VERSION 5.7 ;
  NOWIREEXTENSIONATPIN ON ;
  DIVIDERCHAR "/" ;
  BUSBITCHARS "[]" ;
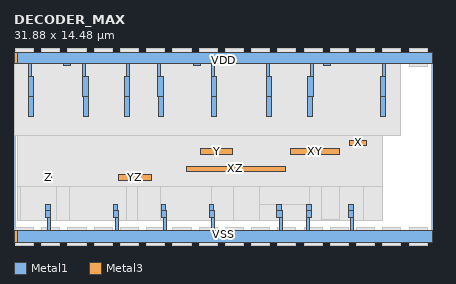
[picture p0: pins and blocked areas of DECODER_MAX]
MACRO DECODER_MAX
  CLASS BLOCK ;
  FOREIGN DECODER_MAX ;
  ORIGIN 1.260 0.000 ;
  SIZE 31.880 BY 14.480 ;
  PIN VSS
    DIRECTION INOUT ;
    USE GROUND ;
    PORT
      LAYER Metal1 ;
        RECT 1.140 2.380 1.500 2.880 ;
        RECT 6.300 2.380 6.660 2.880 ;
        RECT 9.960 2.380 10.320 2.880 ;
        RECT 13.620 2.380 13.980 2.880 ;
        RECT 18.780 2.380 19.140 2.880 ;
        RECT 21.060 2.380 21.420 2.880 ;
        RECT 1.140 1.880 1.530 2.380 ;
        RECT 6.300 1.880 6.690 2.380 ;
        RECT 9.960 1.880 10.350 2.380 ;
        RECT 13.620 1.880 14.010 2.380 ;
        RECT 18.780 1.880 19.170 2.380 ;
        RECT 1.300 0.900 1.530 1.880 ;
        RECT 6.460 0.900 6.690 1.880 ;
        RECT 10.120 0.900 10.350 1.880 ;
        RECT 13.780 0.900 14.010 1.880 ;
        RECT 18.940 0.900 19.170 1.880 ;
        RECT 21.030 1.880 21.420 2.380 ;
        RECT 24.220 2.380 24.580 2.880 ;
        RECT 24.220 1.880 24.610 2.380 ;
        RECT 21.030 0.900 21.260 1.880 ;
        RECT 24.380 0.900 24.610 1.880 ;
        RECT -1.000 0.000 30.620 0.900 ;
      LAYER Metal3 ;
        RECT -1.260 0.000 30.620 0.900 ;
    END
  END VSS
  PIN VDD
    DIRECTION INOUT ;
    USE POWER ;
    PORT
      LAYER Metal1 ;
        RECT -1.000 13.580 30.620 14.480 ;
        RECT -0.190 12.600 0.040 13.580 ;
        RECT 2.550 13.480 3.030 13.580 ;
        RECT 3.990 12.600 4.220 13.580 ;
        RECT 7.340 12.600 7.570 13.580 ;
        RECT -0.190 11.100 0.200 12.600 ;
        RECT 3.990 11.100 4.380 12.600 ;
        RECT -0.160 9.600 0.200 11.100 ;
        RECT 4.020 9.600 4.380 11.100 ;
        RECT 7.180 11.100 7.570 12.600 ;
        RECT 9.710 12.600 9.940 13.580 ;
        RECT 12.450 13.480 12.930 13.580 ;
        RECT 13.770 12.600 14.000 13.580 ;
        RECT 17.950 12.600 18.180 13.580 ;
        RECT 21.300 12.600 21.530 13.580 ;
        RECT 22.350 13.480 22.830 13.580 ;
        RECT 26.860 12.600 27.090 13.580 ;
        RECT 9.710 11.100 10.100 12.600 ;
        RECT 13.770 11.100 14.160 12.600 ;
        RECT 17.950 11.100 18.340 12.600 ;
        RECT 7.180 9.600 7.540 11.100 ;
        RECT 9.740 9.600 10.100 11.100 ;
        RECT 13.800 9.600 14.160 11.100 ;
        RECT 17.980 9.600 18.340 11.100 ;
        RECT 21.140 11.100 21.530 12.600 ;
        RECT 26.700 11.100 27.090 12.600 ;
        RECT 21.140 9.600 21.500 11.100 ;
        RECT 26.700 9.600 27.060 11.100 ;
      LAYER Metal3 ;
        RECT -1.260 13.580 30.620 14.480 ;
    END
  END VDD
  PIN Z
    DIRECTION OUTPUT ;
    ANTENNADIFFAREA 1.760000 ;
    PORT
      LAYER Metal3 ;
      RECT 1.200 4.720 1.600 5.120 ;
    END
  END Z
  PIN YZ
    DIRECTION INPUT ;
    ANTENNAGATEAREA 8.000000 ;
    PORT
      LAYER Metal3 ;
      RECT 6.730 4.720 9.230 5.120 ;
    END
  END YZ
  PIN XZ
    DIRECTION INPUT ;
    ANTENNAGATEAREA 8.000000 ;
    PORT
      LAYER Metal3 ;
      RECT 11.850 5.380 19.450 5.780 ;
    END
  END XZ
  PIN Y
    DIRECTION OUTPUT ;
    ANTENNADIFFAREA 1.760000 ;
    PORT
      LAYER Metal3 ;
      RECT 12.990 6.700 15.390 7.100 ;
    END
  END Y
  PIN XY
    DIRECTION INPUT ;
    ANTENNAGATEAREA 8.000000 ;
    PORT
      LAYER Metal3 ;
      RECT 19.810 6.700 23.510 7.100 ;
    END
  END XY
  PIN X
    DIRECTION OUTPUT ;
    ANTENNADIFFAREA 1.980000 ;
    PORT
      LAYER Metal3 ;
      RECT 24.310 7.360 25.610 7.760 ;
    END
  END X
  OBS
      LAYER Via1 ;
        RECT -1.150 -0.240 0.230 1.140 ;
        RECT 0.850 -0.240 2.230 1.140 ;
        RECT 2.850 -0.240 4.230 1.140 ;
        RECT 4.850 -0.240 6.230 1.140 ;
        RECT 6.850 -0.240 8.230 1.140 ;
        RECT 8.850 -0.240 10.230 1.140 ;
        RECT 10.850 -0.240 12.230 1.140 ;
        RECT 12.850 -0.240 14.230 1.140 ;
        RECT 14.850 -0.240 16.230 1.140 ;
        RECT 16.850 -0.240 18.230 1.140 ;
        RECT 18.850 -0.240 20.230 1.140 ;
        RECT 20.850 -0.240 22.230 1.140 ;
        RECT 22.850 -0.240 24.230 1.140 ;
        RECT 24.850 -0.240 26.230 1.140 ;
        RECT 26.850 -0.240 28.230 1.140 ;
        RECT 28.850 -0.240 30.230 1.140 ;
        RECT -1.010 1.650 26.860 12.830 ;
        RECT -1.150 13.340 0.230 14.720 ;
        RECT 0.850 13.340 2.230 14.720 ;
        RECT 2.850 13.340 4.230 14.720 ;
        RECT 4.850 13.340 6.230 14.720 ;
        RECT 6.850 13.340 8.230 14.720 ;
        RECT 8.850 13.340 10.230 14.720 ;
        RECT 10.850 13.340 12.230 14.720 ;
        RECT 12.850 13.340 14.230 14.720 ;
        RECT 14.850 13.340 16.230 14.720 ;
        RECT 16.850 13.340 18.230 14.720 ;
        RECT 18.850 13.340 20.230 14.720 ;
        RECT 20.850 13.340 22.230 14.720 ;
        RECT 22.850 13.340 24.230 14.720 ;
        RECT 24.850 13.340 26.230 14.720 ;
        RECT 26.850 13.340 28.230 14.720 ;
        RECT 28.850 13.340 30.230 14.720 ;
      LAYER Via2 ;
        RECT -1.150 -0.240 0.230 1.140 ;
        RECT 0.850 -0.240 2.230 1.140 ;
        RECT 2.850 -0.240 4.230 1.140 ;
        RECT 4.850 -0.240 6.230 1.140 ;
        RECT 6.850 -0.240 8.230 1.140 ;
        RECT 8.850 -0.240 10.230 1.140 ;
        RECT 10.850 -0.240 12.230 1.140 ;
        RECT 12.850 -0.240 14.230 1.140 ;
        RECT 14.850 -0.240 16.230 1.140 ;
        RECT 16.850 -0.240 18.230 1.140 ;
        RECT 18.850 -0.240 20.230 1.140 ;
        RECT 20.850 -0.240 22.230 1.140 ;
        RECT 22.850 -0.240 24.230 1.140 ;
        RECT 24.850 -0.240 26.230 1.140 ;
        RECT 26.850 -0.240 28.230 1.140 ;
        RECT 28.850 -0.240 30.230 1.140 ;
        RECT 22.155 1.700 23.515 4.540 ;
        RECT 5.115 7.940 6.475 11.780 ;
        RECT -1.010 4.230 26.810 11.780 ;
        RECT -1.150 13.340 0.230 14.720 ;
        RECT 0.850 13.340 2.230 14.720 ;
        RECT 2.850 13.340 4.230 14.720 ;
        RECT 4.850 13.340 6.230 14.720 ;
        RECT 6.850 13.340 8.230 14.720 ;
        RECT 8.850 13.340 10.230 14.720 ;
        RECT 10.850 13.340 12.230 14.720 ;
        RECT 12.850 13.340 14.230 14.720 ;
        RECT 14.850 13.340 16.230 14.720 ;
        RECT 16.850 13.340 18.230 14.720 ;
        RECT 18.850 13.340 20.230 14.720 ;
        RECT 20.850 13.340 22.230 14.720 ;
        RECT 22.850 13.340 24.230 14.720 ;
        RECT 24.850 13.340 26.230 14.720 ;
        RECT 26.850 13.340 28.230 14.720 ;
        RECT 28.850 13.340 30.230 14.720 ;
      LAYER Metal1 ;
        RECT 8.145 1.650 10.120 6.640 ;
        RECT 15.465 1.650 17.440 6.640 ;
        RECT 25.400 6.500 26.860 9.610 ;
        RECT -0.730 1.650 2.015 12.830 ;
        RECT 2.985 1.650 7.340 12.830 ;
        RECT 9.940 1.650 13.780 12.830 ;
        RECT 14.000 4.520 15.975 12.830 ;
        RECT 17.480 2.870 21.300 12.830 ;
        RECT 21.260 1.650 25.360 12.830 ;
      LAYER Metal2 ;
        RECT -1.150 -0.240 0.230 1.140 ;
        RECT 0.850 -0.240 2.230 1.140 ;
        RECT 2.850 -0.240 4.230 1.140 ;
        RECT 4.850 -0.240 6.230 1.140 ;
        RECT 6.850 -0.240 8.230 1.140 ;
        RECT 8.850 -0.240 10.230 1.140 ;
        RECT 10.850 -0.240 12.230 1.140 ;
        RECT 12.850 -0.240 14.230 1.140 ;
        RECT 14.850 -0.240 16.230 1.140 ;
        RECT 16.850 -0.240 18.230 1.140 ;
        RECT 18.850 -0.240 20.230 1.140 ;
        RECT 20.850 -0.240 22.230 1.140 ;
        RECT 22.850 -0.240 24.230 1.140 ;
        RECT 24.850 -0.240 26.230 1.140 ;
        RECT 26.850 -0.240 28.230 1.140 ;
        RECT 28.850 -0.240 30.230 1.140 ;
        RECT 22.155 1.700 23.515 4.540 ;
        RECT 5.115 7.940 6.475 11.780 ;
        RECT -1.010 4.230 26.810 11.780 ;
        RECT -1.150 13.340 0.230 14.720 ;
        RECT 0.850 13.340 2.230 14.720 ;
        RECT 2.850 13.340 4.230 14.720 ;
        RECT 4.850 13.340 6.230 14.720 ;
        RECT 6.850 13.340 8.230 14.720 ;
        RECT 8.850 13.340 10.230 14.720 ;
        RECT 10.850 13.340 12.230 14.720 ;
        RECT 12.850 13.340 14.230 14.720 ;
        RECT 14.850 13.340 16.230 14.720 ;
        RECT 16.850 13.340 18.230 14.720 ;
        RECT 18.850 13.340 20.230 14.720 ;
        RECT 20.850 13.340 22.230 14.720 ;
        RECT 22.850 13.340 24.230 14.720 ;
        RECT 24.850 13.340 26.230 14.720 ;
        RECT 26.850 13.340 28.230 14.720 ;
        RECT 28.850 13.340 30.230 14.720 ;
      LAYER Nwell ;
        RECT -1.260 8.120 28.160 14.480 ;
  END
END DECODER_MAX
